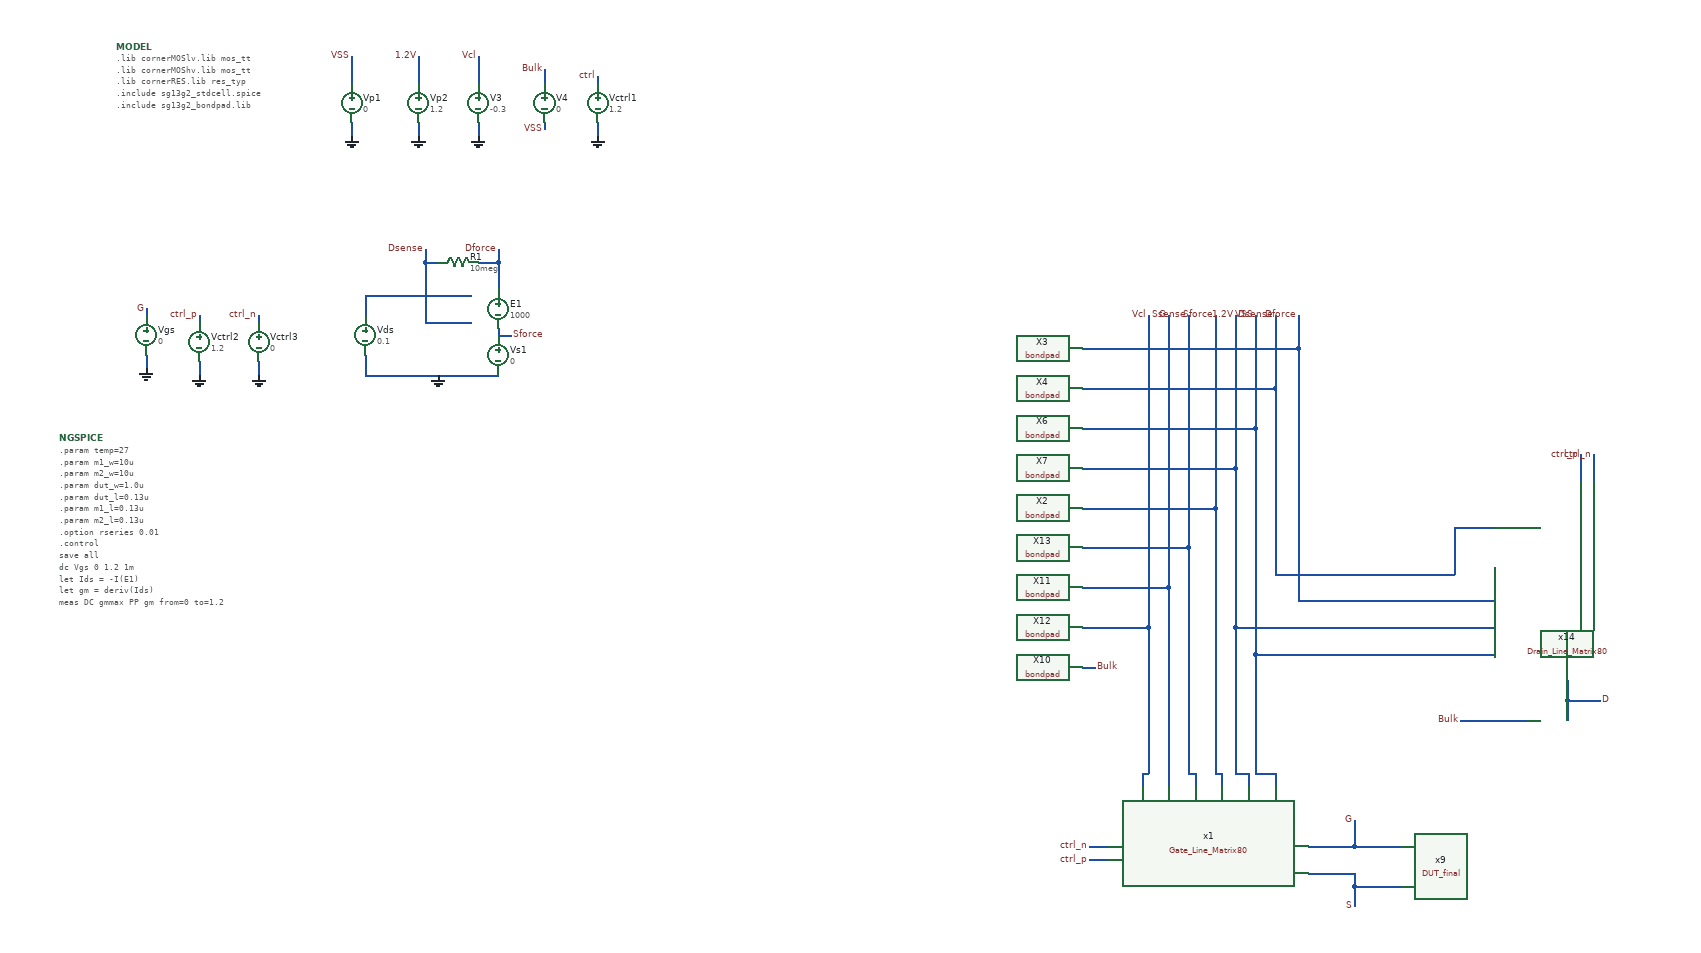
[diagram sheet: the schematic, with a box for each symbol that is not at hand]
v {xschem version=3.4.6 file_version=1.2}
G {}
K {}
V {}
S {}
E {}
B 2 395 -925 1195 -525 {flags=graph

y2=1.2
ypos1=0
ypos2=2
divy=5
subdivy=1
unity=1
x1=-0.3
x2=0.9
divx=5
subdivx=1

dataset=-1
unitx=1
logx=0
logy=0


y1=-0.3
rainbow=0

color="6 7"
node="V(G1)

V(G2)"}
B 2 395 -1355 1195 -955 {flags=graph

y2=0.11
ypos1=0
ypos2=2
divy=5
subdivy=4
unity=1
x1=-0.3
x2=0.9
divx=5
subdivx=1

dataset=-1
unitx=1
logx=0
logy=0


y1=0.099
rainbow=0



color="4 9 7"
node="D2
Dsense
Dforce"}
B 2 395 -505 1195 -105 {flags=graph

y2=0.00021
ypos1=0
ypos2=2
divy=5
subdivy=4
unity=1
x1=-0.3
x2=0.9
divx=5
subdivx=1

dataset=-1
unitx=1
logx=0
logy=0


y1=-4.4e-10
rainbow=0

color="6 4"
node="i(Ids)
i(gm)"
mode=Line}
N 520 -1830 520 -1810 {
lab=GND}
N 520 -1930 520 -1890 {
lab=1.2V}
N 610 -1830 610 -1810 {
lab=GND}
N 610 -1930 610 -1890 {
lab=Vcl}
N 420 -1930 420 -1890 {
lab=VSS}
N 710 -1910 710 -1890 {lab=Bulk}
N 420 -1830 420 -1810 {lab=GND}
N 710 -1830 710 -1820 {lab=VSS}
N 440 -1570 600 -1570 {lab=#net1}
N 610 -1620 640 -1620 {lab=Dforce}
N 640 -1620 640 -1580 {lab=Dforce}
N 640 -1640 640 -1620 {lab=Dforce}
N 530 -1620 550 -1620 {lab=Dsense}
N 530 -1620 530 -1530 {lab=Dsense}
N 530 -1530 600 -1530 {lab=Dsense}
N 530 -1640 530 -1620 {lab=Dsense}
N 640 -1510 660 -1510 {lab=Sforce}
N 640 -1520 640 -1510 {lab=Sforce}
N 440 -1450 640 -1450 {lab=GND}
N 440 -1480 440 -1450 {lab=GND}
N 440 -1570 440 -1540 {lab=#net1}
N 2270 -1330 2270 -1290 {lab=ctrl_p}
N 2290 -1330 2290 -1290 {lab=ctrl_n}
N 1530 -740 1560 -740 {lab=ctrl_n}
N 1530 -720 1560 -720 {lab=ctrl_p}
N 790 -1830 790 -1810 {
lab=GND}
N 790 -1900 790 -1890 {
lab=ctrl}
N 110 -1480 110 -1460 {
lab=GND}
N 110 -1550 110 -1540 {
lab=G}
N 190 -1470 190 -1450 {
lab=GND}
N 190 -1540 190 -1530 {
lab=ctrl_p}
N 280 -1470 280 -1450 {
lab=GND}
N 280 -1540 280 -1530 {
lab=ctrl_n}
N 1520 -1010 1540 -1010 {lab=Bulk}
N 1520 -1250 1720 -1250 {lab=Sforce}
N 1520 -1190 1680 -1190 {lab=Ssense}
N 1520 -1130 1650 -1130 {lab=G}
N 1520 -1070 1620 -1070 {lab=Vcl}
N 1620 -1070 1620 -850 {lab=Vcl}
N 1650 -1130 1650 -830 {lab=G}
N 1680 -1190 1680 -850 {lab=Ssense}
N 1720 -1250 1720 -850 {lab=Sforce}
N 1520 -1310 1750 -1310 {lab=1.2V}
N 1520 -1370 1780 -1370 {lab=VSS}
N 1750 -1540 1750 -1310 {lab=1.2V}
N 1620 -1540 1620 -1070 {lab=Vcl}
N 1650 -1540 1650 -1130 {lab=G}
N 1680 -1540 1680 -1190 {lab=Ssense}
N 1720 -1540 1720 -1250 {lab=Sforce}
N 1810 -1430 1810 -1150 {lab=Dsense}
N 1845 -1490 1845 -1110 {lab=Dforce}
N 1810 -1540 1810 -1430 {lab=Dsense}
N 1845 -1540 1845 -1490 {lab=Dforce}
N 1520 -1430 1810 -1430 {lab=Dsense}
N 1520 -1490 1845 -1490 {lab=Dforce}
N 1780 -1030 1780 -850 {lab=VSS}
N 1780 -1540 1780 -1370 {lab=VSS}
N 1750 -1070 2140 -1070 {lab=1.2V}
N 1750 -1070 1750 -850 {lab=1.2V}
N 1750 -1310 1750 -1070 {lab=1.2V}
N 1780 -1030 2140 -1030 {lab=VSS}
N 1780 -1370 1780 -1030 {lab=VSS}
N 1810 -1150 2080 -1150 {lab=Dsense}
N 1845 -1110 2140 -1110 {lab=Dforce}
N 1610 -850 1620 -850 {lab=Vcl}
N 1610 -850 1610 -830 {lab=Vcl}
N 1680 -850 1690 -850 {lab=Ssense}
N 1690 -850 1690 -830 {lab=Ssense}
N 1720 -850 1730 -850 {lab=Sforce}
N 1730 -850 1730 -830 {lab=Sforce}
N 1750 -850 1770 -850 {lab=1.2V}
N 1770 -850 1770 -830 {lab=1.2V}
N 1780 -850 1810 -850 {lab=VSS}
N 1810 -850 1810 -830 {lab=VSS}
N 1930 -740 2000 -740 {lab=G}
N 1930 -780 1930 -740 {lab=G}
N 1860 -740 1930 -740 {lab=G}
N 1860 -700 1930 -700 {lab=S}
N 1930 -700 1930 -680 {lab=S}
N 1930 -680 2000 -680 {lab=S}
N 1930 -680 1930 -650 {lab=S}
N 2090 -930 2190 -930 {lab=Bulk}
N 2250 -960 2250 -930 {lab=D}
N 2250 -960 2300 -960 {lab=D}
N 2250 -990 2250 -960 {lab=D}
N 2080 -1220 2080 -1150 {lab=Dsense}
N 2080 -1220 2140 -1220 {lab=Dsense}
N 2140 -1160 2140 -1110 {lab=Dforce}
N 2140 -1100 2140 -1070 {lab=1.2V}
N 2140 -1040 2140 -1030 {lab=VSS}
C {devices/code_shown.sym} 65 -1945 0 0 {name=MODEL only_toplevel=true
format="tcleval( @value )"
value="
.lib cornerMOSlv.lib mos_tt\\
.lib cornerMOShv.lib mos_tt\\
.lib cornerRES.lib res_typ\\
.include sg13g2_stdcell.spice
.include sg13g2_bondpad.lib
"}
C {devices/code_shown.sym} -20 -1355 0 0 {name=NGSPICE only_toplevel=true 
value="
.param temp=27
.param m1_w=10u
.param m2_w=10u
.param dut_w=1.0u
.param dut_l=0.13u
.param m1_l=0.13u
.param m2_l=0.13u
.option rseries 0.01
.control
save all 
dc Vgs 0 1.2 1m
let Ids = -I(E1)
let gm = deriv(Ids)
meas DC gmmax PP gm from=0 to=1.2
meas dc vmax when gm=gmmax 
meas dc Imax  find Ids when v(g2)=vmax
let b=Imax-gmmax*vmax
let vt= (1.0e-10-b)/gmmax
print vt
write tran_lshift.raw
.endc
"}
C {devices/vsource.sym} 520 -1860 0 0 {name=Vp2 value=1.2}
C {devices/launcher.sym} 225 -135 0 0 {name=h5
descr="load waves" 
tclcommand="xschem raw_read $netlist_dir/tran_lshift.raw dc"
}
C {devices/gnd.sym} 520 -1810 0 0 {name=l1 lab=GND}
C {devices/lab_pin.sym} 520 -1930 1 0 {name=p4 sig_type=std_logic lab=1.2V}
C {devices/lab_pin.sym} 1750 -1540 1 0 {name=p2 sig_type=std_logic lab=1.2V}
C {devices/lab_pin.sym} 1650 -1540 1 0 {name=p6 sig_type=std_logic lab=G}
C {devices/lab_pin.sym} 1620 -1540 1 0 {name=p7 sig_type=std_logic lab=Vcl}
C {devices/vsource.sym} 610 -1860 0 0 {name=V3 value=-0.3}
C {devices/gnd.sym} 610 -1810 0 0 {name=l4 lab=GND}
C {devices/lab_pin.sym} 610 -1930 1 0 {name=p8 sig_type=std_logic lab=Vcl}
C {sg13g2_pr/bondpad.sym} 1480 -1250 3 0 {name=X2
model=bondpad
spiceprefix=X
size=80u
shape=0
padtype=0
}
C {sg13g2_pr/bondpad.sym} 1480 -1490 3 0 {name=X3
model=bondpad
spiceprefix=X
size=80u
shape=0
padtype=0
}
C {sg13g2_pr/bondpad.sym} 1480 -1430 3 0 {name=X4
model=bondpad
spiceprefix=X
size=80u
shape=0
padtype=0
}
C {sg13g2_pr/bondpad.sym} 1480 -1370 3 0 {name=X6
model=bondpad
spiceprefix=X
size=80u
shape=0
padtype=0
}
C {sg13g2_pr/bondpad.sym} 1480 -1310 3 0 {name=X7
model=bondpad
spiceprefix=X
size=80u
shape=0
padtype=0
}
C {devices/vsource.sym} 420 -1860 0 0 {name=Vp1 value=0}
C {devices/lab_pin.sym} 420 -1930 1 0 {name=p22 sig_type=std_logic lab=VSS}
C {devices/lab_pin.sym} 1780 -1540 1 0 {name=p10 sig_type=std_logic lab=VSS}
C {devices/lab_pin.sym} 1680 -1540 1 0 {name=p17 sig_type=std_logic lab=Ssense}
C {devices/lab_pin.sym} 1720 -1540 1 0 {name=p24 sig_type=std_logic lab=Sforce}
C {sg13g2_pr/bondpad.sym} 1480 -1010 3 0 {name=X10
model=bondpad
spiceprefix=X
size=80u
shape=0
padtype=0
}
C {devices/lab_pin.sym} 1540 -1010 2 0 {name=p25 sig_type=std_logic lab=Bulk}
C {devices/vsource.sym} 710 -1860 0 0 {name=V4 value=0}
C {devices/lab_pin.sym} 710 -1910 1 0 {name=p26 sig_type=std_logic lab=Bulk}
C {devices/lab_pin.sym} 710 -1820 3 0 {name=p27 sig_type=std_logic lab=VSS}
C {devices/gnd.sym} 420 -1810 0 0 {name=l2 lab=GND}
C {devices/lab_pin.sym} 1810 -1540 1 0 {name=p13 sig_type=std_logic lab=Dsense}
C {devices/lab_pin.sym} 1845 -1540 1 0 {name=p14 sig_type=std_logic lab=Dforce}
C {devices/lab_pin.sym} 640 -1640 1 0 {name=p18 sig_type=std_logic lab=Dforce}
C {devices/lab_pin.sym} 660 -1510 2 0 {name=p28 sig_type=std_logic lab=Sforce}
C {devices/vsource.sym} 640 -1480 0 0 {name=Vs1 value=0}
C {vcvs.sym} 640 -1550 0 0 {name=E1 value=1000}
C {devices/vsource.sym} 440 -1510 0 0 {name=Vds value=0.1}
C {res.sym} 580 -1620 3 0 {name=R1
value=10meg
footprint=1206
device=resistor
m=1}
C {devices/lab_pin.sym} 530 -1640 1 0 {name=p33 sig_type=std_logic lab=Dsense}
C {devices/gnd.sym} 550 -1450 0 0 {name=l6 lab=GND}
C {devices/lab_pin.sym} 1530 -740 0 0 {name=p5 sig_type=std_logic lab=ctrl_n}
C {devices/vsource.sym} 790 -1860 0 0 {name=Vctrl1 value=1.2}
C {devices/gnd.sym} 790 -1810 0 0 {name=l5 lab=GND}
C {devices/lab_pin.sym} 790 -1900 1 0 {name=p1 sig_type=std_logic lab=ctrl}
C {devices/vsource.sym} 110 -1510 0 0 {name=Vgs value=0}
C {devices/gnd.sym} 110 -1460 0 0 {name=l7 lab=GND}
C {devices/lab_pin.sym} 110 -1550 1 0 {name=p35 sig_type=std_logic lab=G}
C {devices/vsource.sym} 190 -1500 0 0 {name=Vctrl2 value=1.2}
C {devices/gnd.sym} 190 -1450 0 0 {name=l8 lab=GND}
C {devices/lab_pin.sym} 190 -1540 1 0 {name=p11 sig_type=std_logic lab=ctrl_p}
C {devices/vsource.sym} 280 -1500 0 0 {name=Vctrl3 value=0}
C {devices/gnd.sym} 280 -1450 0 0 {name=l9 lab=GND
value=0}
C {devices/lab_pin.sym} 280 -1540 1 0 {name=p12 sig_type=std_logic lab=ctrl_n
value=0}
C {devices/lab_pin.sym} 1530 -720 0 0 {name=p15 sig_type=std_logic lab=ctrl_p}
C {devices/lab_pin.sym} 2290 -1330 1 0 {name=p16 sig_type=std_logic lab=ctrl_n}
C {devices/lab_pin.sym} 2270 -1330 1 0 {name=p19 sig_type=std_logic lab=ctrl_p}
C {sg13g2_pr/bondpad.sym} 1480 -1190 3 0 {name=X13
model=bondpad
spiceprefix=X
size=80u
shape=0
padtype=0
}
C {sg13g2_pr/bondpad.sym} 1480 -1130 3 0 {name=X11
model=bondpad
spiceprefix=X
size=80u
shape=0
padtype=0
}
C {sg13g2_pr/bondpad.sym} 1480 -1070 3 0 {name=X12
model=bondpad
spiceprefix=X
size=80u
shape=0
padtype=0
}
C {/home/designer/shared/verification/simulations/ihp-sg13g2/MissMatch/design_data/xschem/new_tg/Gate_Line_Matrix80.sym} 1710 -720 2 1 {name=x1}
C {DUT_final.sym} 2220 -710 0 0 {name=x9}
C {devices/lab_pin.sym} 1930 -780 1 0 {name=p29 sig_type=std_logic lab=G}
C {devices/lab_pin.sym} 1930 -650 3 0 {name=p3 sig_type=std_logic lab=S}
C {devices/lab_pin.sym} 2090 -930 0 0 {name=p20 sig_type=std_logic lab=Bulk}
C {devices/lab_pin.sym} 2300 -960 2 0 {name=p9 sig_type=std_logic lab=D
}
C {/home/designer/shared/verification/simulations/ihp-sg13g2/MissMatch/design_data/xschem/new_tg/Drain_Line_Matrix80.sym} 2230 -1140 1 0 {name=x14}
